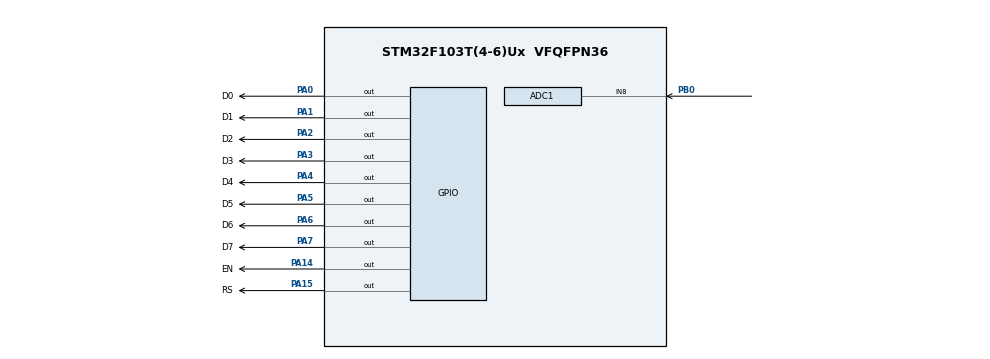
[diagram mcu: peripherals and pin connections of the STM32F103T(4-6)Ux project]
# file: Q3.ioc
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ADC1.Channel-0\#ChannelRegularConversion=ADC_CHANNEL_8
ADC1.NbrOfConversionFlag=1
ADC1.Rank-0\#ChannelRegularConversion=1
ADC1.SamplingTime-0\#ChannelRegularConversion=ADC_SAMPLETIME_1CYCLE_5
ADC1.master=1
Mcu.Family=STM32F1
Mcu.Name=STM32F103T(4-6)Ux
Mcu.Package=VFQFPN36
NVIC.PriorityGroup=NVIC_PRIORITYGROUP_4
PA0-WKUP.GPIO_Label=D0
PA0-WKUP.Signal=GPIO_Output
PA1.GPIO_Label=D1
PA1.Signal=GPIO_Output
PA14.GPIO_Label=EN
PA14.Signal=GPIO_Output
PA15.GPIO_Label=RS
PA15.Signal=GPIO_Output
PA2.GPIO_Label=D2
PA2.Signal=GPIO_Output
PA3.GPIO_Label=D3
PA3.Signal=GPIO_Output
PA4.GPIO_Label=D4
PA4.Signal=GPIO_Output
PA5.GPIO_Label=D5
PA5.Signal=GPIO_Output
PA6.GPIO_Label=D6
PA6.Signal=GPIO_Output
PA7.GPIO_Label=D7
PA7.Signal=GPIO_Output
PB0.Signal=ADCx_IN8
ProjectManager.HeapSize=0x200
ProjectManager.StackSize=0x400
ProjectManager.TargetToolchain=STM32CubeIDE
RCC.AHBFreq_Value=20000000
RCC.APB1Freq_Value=20000000
RCC.APB1TimFreq_Value=20000000
RCC.APB2Freq_Value=20000000
RCC.APB2TimFreq_Value=20000000
RCC.HCLKFreq_Value=20000000
RCC.PLLMUL=RCC_PLL_MUL5
RCC.SYSCLKFreq_VALUE=20000000
RCC.SYSCLKSource=RCC_SYSCLKSOURCE_PLLCLK
RCC.USBFreq_Value=20000000
SH.ADCx_IN8.0=ADC1_IN8,IN8
VP_SYS_VS_ND.Mode=No_Debug
board=custom

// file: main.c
/* USER CODE BEGIN Header */
/**
  ******************************************************************************
  * @file           : main.c
  * @brief          : Main program body
  ******************************************************************************
  * @attention
  *
  * Copyright (c) 2022 STMicroelectronics.
  * All rights reserved.
  *
  * This software is licensed under terms that can be found in the LICENSE file
  * in the root directory of this software component.
  * If no LICENSE file comes with this software, it is provided AS-IS.
  *
  ******************************************************************************
  */
/* USER CODE END Header */
#include "main.h"

/* USER CODE BEGIN Includes */
#include "lcd.h"
/* USER CODE END Includes */

 ADC_HandleTypeDef hadc1;

void SystemClock_Config(void);
static void MX_GPIO_Init(void);
static void MX_ADC1_Init(void);

int main(void)
{

  /* MCU Configuration--------------------------------------------------------*/

  /* Reset of all peripherals, Initializes the Flash interface and the Systick. */
  HAL_Init();

  /* Configure the system clock */
  SystemClock_Config();

  /* Initialize all configured peripherals */
  MX_GPIO_Init();
  MX_ADC1_Init();
  /* USER CODE BEGIN 2 */
  HAL_ADC_Start(&hadc1);
  Lcd_PortType ports[]={D0_GPIO_Port,D1_GPIO_Port,D2_GPIO_Port,D3_GPIO_Port, D4_GPIO_Port, D5_GPIO_Port,D6_GPIO_Port,D7_GPIO_Port};
  Lcd_PinType pins[]={D0_Pin, D1_Pin,D2_Pin,D3_Pin,D4_Pin, D5_Pin,D6_Pin,D7_Pin};
  Lcd_HandleTypeDef lcd = Lcd_create(ports, pins, RS_GPIO_Port, RS_Pin, EN_GPIO_Port, EN_Pin, LCD_8_BIT_MODE);
  /* USER CODE END 2 */

  /* Infinite loop */
  /* USER CODE BEGIN WHILE */
	float input;
	float voltage;
	float pressure;
  while (1)
  {
		HAL_ADC_Start(&hadc1);
		input = HAL_ADC_GetValue(&hadc1);
		voltage = input / 4095.0 *5;
		pressure = 9.051 + 22.23*voltage ;
		Lcd_clear(&lcd);
		Lcd_cursor(&lcd, 0, 0);
		Lcd_float(&lcd, pressure);
		HAL_ADC_Stop(&hadc1);
		HAL_Delay(10);

    /* USER CODE END WHILE */

  }
}

void SystemClock_Config(void)
{
  RCC_OscInitTypeDef RCC_OscInitStruct = {0};
  RCC_ClkInitTypeDef RCC_ClkInitStruct = {0};
  RCC_PeriphCLKInitTypeDef PeriphClkInit = {0};

  /** Initializes the RCC Oscillators according to the specified parameters
  * in the RCC_OscInitTypeDef structure.
  */
  RCC_OscInitStruct.OscillatorType = RCC_OSCILLATORTYPE_HSI;
  RCC_OscInitStruct.HSIState = RCC_HSI_ON;
  RCC_OscInitStruct.HSICalibrationValue = RCC_HSICALIBRATION_DEFAULT;
  RCC_OscInitStruct.PLL.PLLState = RCC_PLL_ON;
  RCC_OscInitStruct.PLL.PLLSource = RCC_PLLSOURCE_HSI_DIV2;
  RCC_OscInitStruct.PLL.PLLMUL = RCC_PLL_MUL5;
  if (HAL_RCC_OscConfig(&RCC_OscInitStruct) != HAL_OK)
  {
    Error_Handler();
  }

  /** Initializes the CPU, AHB and APB buses clocks
  */
  RCC_ClkInitStruct.ClockType = RCC_CLOCKTYPE_HCLK|RCC_CLOCKTYPE_SYSCLK
                              |RCC_CLOCKTYPE_PCLK1|RCC_CLOCKTYPE_PCLK2;
  RCC_ClkInitStruct.SYSCLKSource = RCC_SYSCLKSOURCE_PLLCLK;
  RCC_ClkInitStruct.AHBCLKDivider = RCC_SYSCLK_DIV1;
  RCC_ClkInitStruct.APB1CLKDivider = RCC_HCLK_DIV2;
  RCC_ClkInitStruct.APB2CLKDivider = RCC_HCLK_DIV1;

  if (HAL_RCC_ClockConfig(&RCC_ClkInitStruct, FLASH_LATENCY_0) != HAL_OK)
  {
    Error_Handler();
  }
  PeriphClkInit.PeriphClockSelection = RCC_PERIPHCLK_ADC;
  PeriphClkInit.AdcClockSelection = RCC_ADCPCLK2_DIV2;
  if (HAL_RCCEx_PeriphCLKConfig(&PeriphClkInit) != HAL_OK)
  {
    Error_Handler();
  }
}

static void MX_ADC1_Init(void)
{

  ADC_ChannelConfTypeDef sConfig = {0};

  /** Common config
  */
  hadc1.Instance = ADC1;
  hadc1.Init.ScanConvMode = ADC_SCAN_DISABLE;
  hadc1.Init.ContinuousConvMode = ENABLE;
  hadc1.Init.DiscontinuousConvMode = DISABLE;
  hadc1.Init.ExternalTrigConv = ADC_SOFTWARE_START;
  hadc1.Init.DataAlign = ADC_DATAALIGN_RIGHT;
  hadc1.Init.NbrOfConversion = 1;
  if (HAL_ADC_Init(&hadc1) != HAL_OK)
  {
    Error_Handler();
  }

  /** Configure Regular Channel
  */
  sConfig.Channel = ADC_CHANNEL_8;
  sConfig.Rank = ADC_REGULAR_RANK_1;
  sConfig.SamplingTime = ADC_SAMPLETIME_1CYCLE_5;
  if (HAL_ADC_ConfigChannel(&hadc1, &sConfig) != HAL_OK)
  {
    Error_Handler();
  }

}

static void MX_GPIO_Init(void)
{
  GPIO_InitTypeDef GPIO_InitStruct = {0};

  /* GPIO Ports Clock Enable */
  __HAL_RCC_GPIOA_CLK_ENABLE();
  __HAL_RCC_GPIOB_CLK_ENABLE();

  /*Configure GPIO pin Output Level */
  HAL_GPIO_WritePin(GPIOA, D0_Pin|D1_Pin|D2_Pin|D3_Pin
                          |D4_Pin|D5_Pin|D6_Pin|D7_Pin
                          |EN_Pin|RS_Pin, GPIO_PIN_RESET);

  /*Configure GPIO pins : D0_Pin D1_Pin D2_Pin D3_Pin
                           D4_Pin D5_Pin D6_Pin D7_Pin
                           EN_Pin RS_Pin */
  GPIO_InitStruct.Pin = D0_Pin|D1_Pin|D2_Pin|D3_Pin
                          |D4_Pin|D5_Pin|D6_Pin|D7_Pin
                          |EN_Pin|RS_Pin;
  GPIO_InitStruct.Mode = GPIO_MODE_OUTPUT_PP;
  GPIO_InitStruct.Pull = GPIO_NOPULL;
  GPIO_InitStruct.Speed = GPIO_SPEED_FREQ_LOW;
  HAL_GPIO_Init(GPIOA, &GPIO_InitStruct);

}

void Error_Handler(void)
{
  __disable_irq();
  while (1)
  {
  }
}
